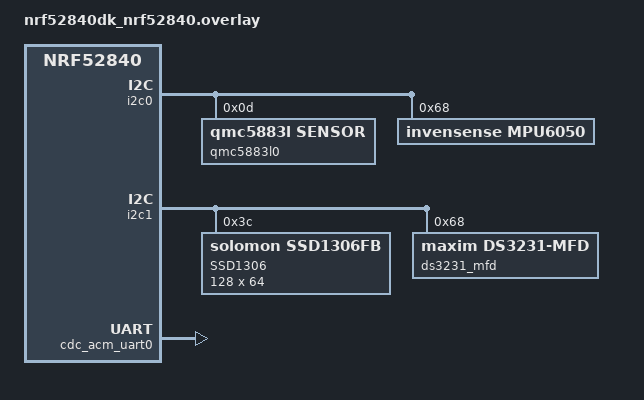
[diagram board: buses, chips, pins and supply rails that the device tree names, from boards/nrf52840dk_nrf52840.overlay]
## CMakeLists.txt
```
cmake_minimum_required(VERSION 3.20.0)

set(ZEPHYR_EXTRA_MODULES "${CMAKE_SOURCE_DIR}/modules/drivers")

find_package(Zephyr REQUIRED HINTS $ENV{ZEPHYR_BASE})

project(smartwatch_test) 

include(${PROJECT_SOURCE_DIR}/src/app/usb_common/usb_common.cmake)

add_subdirectory(src/app/src)
add_subdirectory(src/app/app_update)

target_sources(app PRIVATE src/main.c
                )

target_include_directories(app PRIVATE src/app/include)
```

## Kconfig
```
#this Kconfig is for src directory , external components/modules can be compiled without it
rsource "src/app/src/Kconfig"
rsource "src/app/app_update/Kconfig"

source "Kconfig"
```

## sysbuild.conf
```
# Enable MCUboot bootloader support
SB_CONFIG_BOOTLOADER_MCUBOOT=y
SB_CONFIG_BOOT_SIGNATURE_KEY_FILE="/home/mod/my_private_key.pem"
SB_CONFIG_PARTITION_MANAGER=n
```

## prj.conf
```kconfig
# 1. if Kconfig symbols of board defconfig file needs to modify then use this prj.conf 
# 2. pristine build reset/remove custom K config options so enable them in prj.conf 

#Enable QMC sensor
CONFIG_ENABLE_QMC5883L_SENSOR=y
CONFIG_QMC5883L_RANGE=2000
CONFIG_QMC5883L_ODR=50
CONFIG_QMC5883L_OSR=128

#Enable I2C
CONFIG_I2C=y
CONFIG_SENSOR=y

#Enable GPIO and logging, use logging instead of printk
CONFIG_GPIO=y
#disable logging to use zephyr shell and run commands on shell
CONFIG_LOG=y
#Default level, sets the logging level used by modules that are not setting their own logging level
# log level 0:OFF, 1: ERROR, 2: WARNING ,3: INFO, 4: DEBUG
#CONFIG_LOG_DEFAULT_LEVEL=3    

#Logging in app_sources
CONFIG_ZSW_APP_LOG_LEVEL_WRN=y

#qmc module logging,qmc sensor and zsw app logging set to warning, for usb and ble ota , set to info
CONFIG_SENSOR_LOG_LEVEL_WRN=y

# Enable floating point support for the printf
CONFIG_CBPRINTF_FP_SUPPORT=y

# Enable (FPU) for calculations 
#CONFIG_FPU=y

# NVS
CONFIG_FLASH=y
CONFIG_FLASH_INIT_PRIORITY=40
CONFIG_FLASH_MAP=y
CONFIG_MPU_ALLOW_FLASH_WRITE=y
CONFIG_FLASH_PAGE_LAYOUT=y
CONFIG_STREAM_FLASH=y
CONFIG_STREAM_FLASH_ERASE=y
CONFIG_FLASH_MAP_LABELS=y

#Enable settings to save calibation data of qmc
CONFIG_SETTINGS=y
CONFIG_NVS=y

#Enable own qmc calibration driver,temporay option 
CONFIG_ENABLE_QMC_CALIBRATION=n
CONFIG_USE_RAW_MAGNETOMETER_DATA=y

#Enable built in driver for mpu6050, can enable options in menuconfig but they reset on pristine build
CONFIG_MPU6050=y
CONFIG_MPU6050_TRIGGER_NONE=y
#CONFIG_MPU6050_GYRO_FS=2000  #update version

#Enbale own IMU driver
CONFIG_ENABLE_IMU=y

#update the log buffer size
CONFIG_LOG_BUFFER_SIZE=2048

#Enable built-in driver of ds3231
CONFIG_RTC=y
CONFIG_RTC_DS3231=y
CONFIG_COUNTER=n

#Enable RTC app code
CONFIG_ENABLE_RTC_TIME=y

#Enable display driver
CONFIG_DISPLAY=y
CONFIG_SSD1306=y
CONFIG_DISPLAY_LOG_LEVEL_ERR=y

CONFIG_LV_Z_MEM_POOL_SIZE=16384

#Enable shell for debugging only
CONFIG_LV_Z_SHELL=n
CONFIG_SHELL=n      

CONFIG_LVGL=y
CONFIG_LV_USE_LOG=y
CONFIG_LV_USE_LABEL=y
CONFIG_LV_TXT_ENC_UTF8=y
CONFIG_LV_USE_ARC=n

# LVGL Size optimizations
CONFIG_LV_CONF_MINIMAL=y
CONFIG_LV_LABEL_TEXT_SELECTION=n
CONFIG_LV_LABEL_LONG_TXT_HINT=n

CONFIG_LV_Z_BITS_PER_PIXEL=1

#CONFIG_LV_LOG_LEVEL_TRACE=y
CONFIG_LV_LOG_PRINTF=y

CONFIG_MPU_LOG_LEVEL_OFF=y                  # hides all those mpu_configure_region lines

CONFIG_MAIN_STACK_SIZE=3072

CONFIG_LV_Z_VDB_SIZE=16
CONFIG_LV_Z_FULL_REFRESH=n

CONFIG_LV_FONT_UNSCII_8=y
CONFIG_LV_FONT_DEFAULT_UNSCII_8=y
CONFIG_LV_FONT_MONTSERRAT_14=n
CONFIG_LV_COLOR_DEPTH_1=y 

CONFIG_LV_Z_BUFFER_ALLOC_DYNAMIC=y

CONFIG_ASSERT=y
CONFIG_ASSERT_NO_COND_INFO=y
CONFIG_ASSERT_NO_MSG_INFO=y
CONFIG_ASSERT_VERBOSE=n
CONFIG_BT_ASSERT_VERBOSE=n   # for optimizing the code size

CONFIG_BT=y
CONFIG_BT_PERIPHERAL=y
CONFIG_BT_DEVICE_NAME="Smart_Watch"

CONFIG_SYSTEM_WORKQUEUE_STACK_SIZE=2048

CONFIG_MCUMGR=y
CONFIG_MCUMGR_GRP_IMG=y  #part of app prj.conf as dfu performed from the application,if serial recovery it'll be a part of bootloader prj.conf
CONFIG_ZCBOR=y         # for encode/decode of CBOR
CONFIG_NET_BUF=y

CONFIG_MCUMGR_GRP_OS=y    # enables the OS group in mcumgr, allow CLI tools and aps to execute commands
CONFIG_MCUMGR_GRP_OS_BOOTLOADER_INFO=y  # enables an application to share info about bootloader(version etc) via MCUmgr SMP
CONFIG_IMG_MANAGER=y       # enable FOTA and DFU image management
CONFIG_STREAM_FLASH=y      # enable stream flash, write data to flash using continuous stream of bytes
CONFIG_BOOTLOADER_MCUBOOT=y

# Allow for large Bluetooth data packets.
CONFIG_BT_L2CAP_TX_MTU=498

# BLE packet type(ACL,Isochronous etc)
CONFIG_BT_BUF_ACL_RX_SIZE=502
CONFIG_BT_BUF_ACL_TX_SIZE=502    
CONFIG_BT_CTLR_DATA_LENGTH_MAX=251

# Enable the Bluetooth mcumgr transport (unauthenticated).
CONFIG_MCUMGR_TRANSPORT_BT=y
CONFIG_MCUMGR_TRANSPORT_BT_CONN_PARAM_CONTROL=y #connection parameter control if SMP is used for DFU over ble

# Enable the mcumgr Packet Reassembly feature over Bluetooth and its configuration dependencies.
# MCUmgr buffer size is optimized to fit one SMP packet divided into five Bluetooth Write Commands,
# transmitted with the maximum possible MTU value: 498 bytes.
CONFIG_MCUMGR_TRANSPORT_BT_REASSEMBLY=y
CONFIG_MCUMGR_TRANSPORT_NETBUF_SIZE=2475
CONFIG_MCUMGR_GRP_OS_MCUMGR_PARAMS=y
CONFIG_MCUMGR_TRANSPORT_WORKQUEUE_STACK_SIZE=4608

# Disable Bluetooth ping support
CONFIG_BT_CTLR_LE_PING=n

CONFIG_MCUMGR_TRANSPORT_BT_PERM_RW_AUTHEN=y

#dependencies for dfu over USB CDC ACM
CONFIG_USB_DEVICE_STACK_NEXT=y
CONFIG_STDOUT_CONSOLE=y
CONFIG_SERIAL=y
CONFIG_UART_LINE_CTRL=y
CONFIG_USBD_CDC_ACM_CLASS=y

CONFIG_USBD_LOG_LEVEL_ERR=y
CONFIG_UDC_DRIVER_LOG_LEVEL_ERR=y
CONFIG_USBD_CDC_ACM_LOG_LEVEL_OFF=y

CONFIG_SAMPLE_USBD_PID=0x0001
CONFIG_SAMPLE_USBD_PRODUCT="USBD CDC ACM"

# Configure MCUMGR transport to UART
CONFIG_UART_MCUMGR=y
CONFIG_MCUMGR_TRANSPORT_UART=y

# Configure dependencies for CONFIG_MCUMGR  
CONFIG_CRC=y

# Configure dependencies for CONFIG_MCUMGR_TRANSPORT_UART 
CONFIG_BASE64=y

#custom Kconfig options to enable dfu
CONFIG_DFU_SUPPORT_ENABLE=y
```

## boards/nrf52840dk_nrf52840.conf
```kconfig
#Enable QSPI driver NOR flash memory driver 
CONFIG_NORDIC_QSPI_NOR=y   
```

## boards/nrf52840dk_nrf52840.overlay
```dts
/delete-node/ &boot_partition;
/delete-node/ &slot0_partition;
/delete-node/ &slot1_partition;

/ {
    aliases {
        qmc5883l-dev = &qmc5883l0;   /* alias = qmc5883l-dev -> becomes _ in C macros */
        mpu6050-dev = &mpu6050;
        rtc = &ds3231_rtc;
    };

    chosen {
		zephyr,display = &ssd1306;

        /* Choose CDC ACM for mcumgr */
        zephyr,uart-mcumgr = &cdc_acm_uart0;  /*virtual uart is used for mcumgr, in same way could also be used for console */
	};
};

&i2c0 {                 /*scl = 27 , sda =26 */
    qmc5883l0: qmc5883l@d {      /* node-label : node-name, version update */
        compatible = "qmc5883l,sensor";
        reg = <0x0D>;
    };

    mpu6050: mpu6050@68 {
		compatible = "invensense,mpu6050";
		reg = <0x68>;
		status = "okay";
	};
};

&i2c1 {
    status = "okay";        /* enable the bus,i2c1 SDA= 30, SCL =31*/

   ssd1306: ssd1306@3c {
		compatible = "solomon,ssd1306fb";
		reg = <0x3c>;
		label = "SSD1306";
		width  = <128>;
		height = <64>;
		segment-offset  = <0>;
		page-offset     = <0>;
		display-offset  = <10>;
		multiplex-ratio = <63>;
		segment-remap;
		com-invdir;
        com-sequential;
		prechargep = <0x11>;
	};

    ds3231_mfd: ds3231@68 {
        compatible = "maxim,ds3231-mfd";
        reg = <0x68>;
        status = "okay";

        /* The RTC is now a child of the MFD node */
        ds3231_rtc: rtc {
            compatible = "maxim,ds3231-rtc";
            status = "okay";
            isw-gpios = <&gpio0 0 (GPIO_PULL_UP | GPIO_ACTIVE_LOW)>;
        };

        /* Optional: Enable the internal temperature sensor */
        ds3231_sensor: sensor {
            compatible = "maxim,ds3231-sensor";
            status = "okay";
        };

    };

};

&zephyr_udc0 {
	cdc_acm_uart0: cdc_acm_uart0 {
		compatible = "zephyr,cdc-acm-uart"; /*cdc acm virtual uart emulate over usb, it has no connection with hardware uart */
		label = "Zephyr USB CDC-ACM";
	};
};

&flash0 {
	partitions {

		ranges;
		#address-cells = <1>;
		#size-cells = <1>;

		boot_partition: partition@0 {
			compatible = "zephyr,mapped-partition";  /* CPU mapped address indicate that it is a part of SoC*/
			label = "mcuboot";
			reg = <0x000000000 0x00010000>;
		};

		slot0_partition: partition@10000 {
			compatible = "zephyr,mapped-partition";
			label = "image-0";
			reg = <0x000010000 0x0000e8000>;
		};
	};
};

/* STEP 2.1 - Add external flash to board conf file */
&mx25r64 {
	partitions {
		compatible = "fixed-partitions";    /*fixed partition used for external flash, it is external to SoC */
		#address-cells = <1>;       /* 1 represents 32-bit address, 2 (64-bit address) */
		#size-cells = <1>;

		slot1_partition: partition@0 {
			label = "image-1";
			reg = <0x000000000 0x0000e8000>;
		};
	};
};
```

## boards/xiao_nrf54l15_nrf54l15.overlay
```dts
/ {
    aliases {
        qmc5883l-dev = &qmc5883l0;   /* alias = qmc5883l-dev -> becomes _ in C macros */
        rtc = &ds3231_rtc;
    };

    chosen {
		zephyr,display = &ssd1306;
	};
};

&xiao_i2c {
    status = "okay";        /* enable the bus,i2c1 SDA= 30, SCL =31*/
	
   ssd1306: ssd1306@3c {
		compatible = "solomon,ssd1306fb";
		reg = <0x3c>;
		label = "SSD1306";
		width  = <128>;
		height = <64>;
		segment-offset  = <0>;
		page-offset     = <0>;
		display-offset  = <10>;
		multiplex-ratio = <63>;
		segment-remap;
		com-invdir;
        com-sequential;
		prechargep = <0x11>;
	};

    ds3231_mfd: ds3231@68 {
        compatible = "maxim,ds3231-mfd";
        reg = <0x68>;
        status = "okay";

        /* The RTC is now a child of the MFD node */
        ds3231_rtc: rtc {
            compatible = "maxim,ds3231-rtc";
            status = "okay";
            isw-gpios = <&gpio0 0 (GPIO_PULL_UP | GPIO_ACTIVE_LOW)>;
        };
        
        /* Optional: Enable the internal temperature sensor */
        ds3231_sensor: sensor {
            compatible = "maxim,ds3231-sensor";
            status = "okay";
        };

    };  
    
    qmc5883l0: qmc5883l@0d {
        compatible = "qmc5883l,sensor";
        reg = <0x0D>;
    };

};

 
```

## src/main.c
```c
#include <zephyr/kernel.h>
#include <zephyr/drivers/gpio.h>
#include <stdio.h>
#include <zephyr/device.h>
#include <zephyr/devicetree.h>
#include <zephyr/drivers/sensor.h>
#include <zephyr/drivers/sensor_data_types.h>
#include "magnetometer.h"
#include "imu.h"
#include "sensor_fusion.h"
#include "rtc_time.h"
#include "watch_display.h"
#include "app_update.h"
#include <zephyr/logging/log.h>

LOG_MODULE_REGISTER(main);

#define SLEEP_TIME_MS 100U

int main(void)
{       int ret;
        char buff1[30] = {0};
        char buff2[20] = {0};

        const char* mag_direction = NULL;

        #ifdef CONFIG_ENABLE_QMC5883L_SENSOR
        

        #ifdef CONFIG_ENABLE_QMC_CALIBRATION
        int64_t start = k_uptime_get();
        #endif

         /*wait for serial display*/
        k_sleep(K_MSEC(1000));

        #ifdef CONFIG_DFU_SUPPORT_ENABLE
        ret = app_update_init(); /*init usb and ble for dfu*/
        if (ret != 0)
        {
                LOG_INF("DFU init failed");
                return 0;
        }
        #endif
        
        ret = init_magnetometer();
         if (ret!=0)
        {
                LOG_INF("magnetometer init fail");
                return 0;
        }

        #ifdef CONFIG_ENABLE_QMC_CALIBRATION
        /*test calibration of qmc sensor*/
        ret = start_magn_calibration();
        if(ret!=0){
                printk("calibration start fail\n");
                return 0;
        } 

        /*calibrate for 50s*/
        while (k_uptime_get() - start < 50000) {
        ret = read_magn_with_calibration(&mag_x, &mag_y, &mag_z); /*TODO: revist as no need of pass parameters here as during calibration , values of sensor are not updated , just max and min values are updated*/
        if(ret!=0){
                printk("unable to perform calibration\n");
                return 0;
        } 
        k_sleep(K_MSEC(100));
        }
        zsw_magnetometer_stop_calibration();
        #endif

        #endif
        #ifdef CONFIG_ENABLE_IMU
        
        k_msleep(150);  // wait 150ms after init

        ret = init_mpu6050();
        if (ret!=0)
        {
                LOG_INF("mpu6050 init failed");
                return 0;
        }
       
        sensor_fusion_init();

        #endif

        #ifdef CONFIG_ENABLE_RTC_TIME
        /*init rtc and set initial time*/
        ret = ds3231_rtc_init();
        if (ret!=0)
        {
                LOG_INF("rtc init failed");
                return 0;
        }   
        #endif
        
        ret = watch_display_init();  /*init oled display*/
        if (ret!=0)
        {
                LOG_INF("display init failed");
                return 0;
        }

        /*create display screen via lvgl*/
        create_screen1();  
        
        #ifdef CONFIG_ENABLE_IMU
        create_screen2();
        #endif

        /* load screen1 initally*/
        lv_scr_load(screen1);

        lv_timer_handler();
       
        while(1)
        { 

                #ifdef CONFIG_ENABLE_IMU
                mag_direction = get_direction();
                k_sleep(K_MSEC(1000)); //k_sleep(K_MSEC(10)); //used to test sensor fusion
              
                #endif

                #ifdef CONFIG_ENABLE_RTC_TIME
                rtc_get_date_time();
                #endif

                /*display time on watch*/
                sprintf(buff1, "%02d:%02d:%02d",tm.tm_hour, tm.tm_min, tm.tm_sec);
                lv_label_set_text(rtc_label, buff1);

                k_sleep(K_MSEC(100));
                
                #ifdef CONFIG_ENABLE_IMU
                switch_screens();
                /*display direction*/
                sprintf(buff2,"%s", mag_direction);
                lv_label_set_text(direction_label, buff2);
                #endif
                lv_timer_handler();

                k_sleep(K_MSEC(1000));
        }
        
        return 0;

}

/*target : print RTC time on one screen and magnetic direction on screen2

 1. get RTC time and display
 2. get direction and display
 
 
 int main()
 {
 if enable qmc (qmc init)
 if qmc calibration enable(perform calibration)
 if enable imu (init mpu , init sensor fusion)
 if rtc enable : rtc init

 init zephyr display
 turn off display
 create screen1 and 2

 load screen1
 lv time handler

   while(1)
   {
     read rtc and get direction

     set lvgl text for rtc and direction
     
   }
 
 } 
   
 create screen1()
 { 
    create screen and dynamic label

 }
 
 */
```
